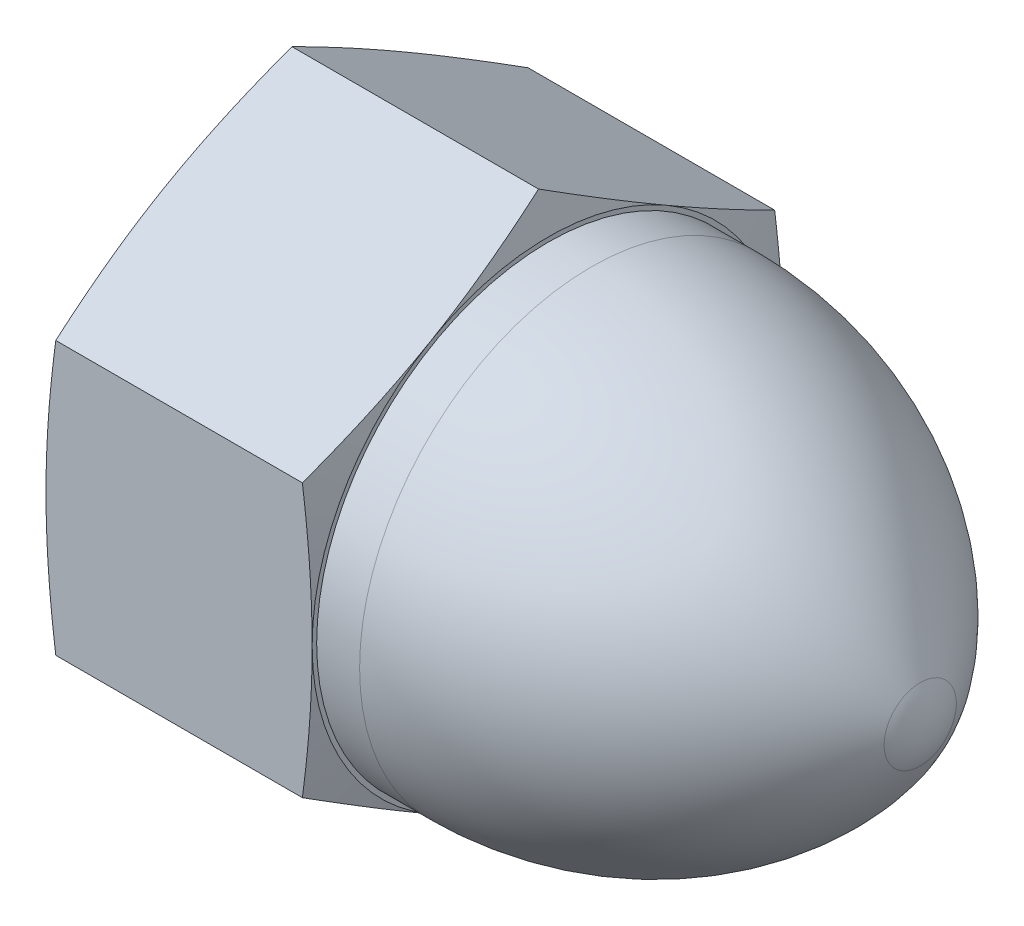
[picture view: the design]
ISO-10303-21;
HEADER;
FILE_DESCRIPTION(('STEP AP214'),'2;1');
FILE_NAME('part.step','',(''),(''),'','','');
FILE_SCHEMA(('AUTOMOTIVE_DESIGN { 1 0 10303 214 1 1 1 1 }'));
ENDSEC;
DATA;
#1=APPLICATION_CONTEXT('core data for automotive mechanical design processes');
#2=APPLICATION_PROTOCOL_DEFINITION('international standard','automotive_design',2000,#1);
#3=PRODUCT_CONTEXT('',#1,'mechanical');
#4=PRODUCT('Part','Part','',(#3));
#5=PRODUCT_RELATED_PRODUCT_CATEGORY('part','',(#4));
#6=PRODUCT_DEFINITION_FORMATION('','',#4);
#7=PRODUCT_DEFINITION_CONTEXT('part definition',#1,'design');
#8=PRODUCT_DEFINITION('design','',#6,#7);
#9=PRODUCT_DEFINITION_SHAPE('','',#8);
#10=(LENGTH_UNIT() NAMED_UNIT(*) SI_UNIT(.MILLI.,.METRE.));
#11=(NAMED_UNIT(*) PLANE_ANGLE_UNIT() SI_UNIT($,.RADIAN.));
#12=(NAMED_UNIT(*) SI_UNIT($,.STERADIAN.) SOLID_ANGLE_UNIT());
#13=UNCERTAINTY_MEASURE_WITH_UNIT(LENGTH_MEASURE(1.E-05),#10,'distance_accuracy_value','');
#14=(GEOMETRIC_REPRESENTATION_CONTEXT(3) GLOBAL_UNCERTAINTY_ASSIGNED_CONTEXT((#13)) GLOBAL_UNIT_ASSIGNED_CONTEXT((#10,
#11,#12)) REPRESENTATION_CONTEXT('',''));
#15=CARTESIAN_POINT('',(0.,0.,0.));
#16=DIRECTION('',(0.,0.,1.));
#17=DIRECTION('',(1.,0.,0.));
#18=AXIS2_PLACEMENT_3D('',#15,#16,#17);
#19=CARTESIAN_POINT('',(20.574,21.0805017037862,0.));
#20=DIRECTION('',(-1.,0.,0.));
#21=DIRECTION('',(0.,0.,1.));
#22=AXIS2_PLACEMENT_3D('',#19,#20,#21);
#23=PLANE('',#22);
#24=CARTESIAN_POINT('',(20.574,0.,0.));
#25=DIRECTION('',(-1.,0.,0.));
#26=DIRECTION('',(0.,0.,1.));
#27=AXIS2_PLACEMENT_3D('',#24,#25,#26);
#28=CIRCLE('',#27,17.907);
#29=CARTESIAN_POINT('',(20.574,0.,17.907));
#30=VERTEX_POINT('',#29);
#31=EDGE_CURVE('E308',#30,#30,#28,.F.);
#32=ORIENTED_EDGE('',*,*,#31,.F.);
#33=EDGE_LOOP('',(#32));
#34=FACE_BOUND('',#33,.T.);
#35=CARTESIAN_POINT('',(20.574,0.,0.));
#36=DIRECTION('',(-1.,0.,0.));
#37=DIRECTION('',(0.,0.,1.));
#38=AXIS2_PLACEMENT_3D('',#35,#36,#37);
#39=CIRCLE('',#38,18.25625);
#40=CARTESIAN_POINT('',(20.574,0.,18.25625));
#41=VERTEX_POINT('',#40);
#42=CARTESIAN_POINT('',(20.574,15.8103762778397,9.12812499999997));
#43=VERTEX_POINT('',#42);
#44=EDGE_CURVE('E279',#41,#43,#39,.T.);
#45=ORIENTED_EDGE('',*,*,#44,.F.);
#46=CARTESIAN_POINT('',(20.574,0.,0.));
#47=DIRECTION('',(-1.,0.,0.));
#48=DIRECTION('',(0.,0.,1.));
#49=AXIS2_PLACEMENT_3D('',#46,#47,#48);
#50=CIRCLE('',#49,18.25625);
#51=CARTESIAN_POINT('',(20.574,-15.8103762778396,9.12812500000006));
#52=VERTEX_POINT('',#51);
#53=EDGE_CURVE('E44',#52,#41,#50,.T.);
#54=ORIENTED_EDGE('',*,*,#53,.F.);
#55=CARTESIAN_POINT('',(20.574,-15.8103762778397,-9.12812499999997));
#56=VERTEX_POINT('',#55);
#57=EDGE_CURVE('E302',#56,#52,#50,.T.);
#58=ORIENTED_EDGE('',*,*,#57,.F.);
#59=CARTESIAN_POINT('',(20.574,0.,-18.25625));
#60=VERTEX_POINT('',#59);
#61=EDGE_CURVE('E360',#60,#56,#50,.T.);
#62=ORIENTED_EDGE('',*,*,#61,.F.);
#63=CARTESIAN_POINT('',(20.574,15.8103762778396,-9.12812500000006));
#64=VERTEX_POINT('',#63);
#65=EDGE_CURVE('E42',#64,#60,#50,.T.);
#66=ORIENTED_EDGE('',*,*,#65,.F.);
#67=EDGE_CURVE('E11',#43,#64,#50,.T.);
#68=ORIENTED_EDGE('',*,*,#67,.F.);
#69=EDGE_LOOP('',(#45,#54,#58,#62,#66,#68));
#70=FACE_BOUND('',#69,.T.);
#71=ADVANCED_FACE('F32',(#34,#70),#23,.F.);
#72=CARTESIAN_POINT('',(0.,0.,0.));
#73=DIRECTION('',(-1.,0.,0.));
#74=DIRECTION('',(0.,0.,1.));
#75=AXIS2_PLACEMENT_3D('',#72,#73,#74);
#76=CYLINDRICAL_SURFACE('',#75,17.907);
#77=CARTESIAN_POINT('',(23.8938672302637,0.,0.));
#78=DIRECTION('',(-1.,0.,0.));
#79=DIRECTION('',(0.,0.,1.));
#80=AXIS2_PLACEMENT_3D('',#77,#78,#79);
#81=CIRCLE('',#80,17.907);
#82=CARTESIAN_POINT('',(23.8938672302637,0.,17.907));
#83=VERTEX_POINT('',#82);
#84=EDGE_CURVE('E326',#83,#83,#81,.T.);
#85=ORIENTED_EDGE('',*,*,#84,.T.);
#86=EDGE_LOOP('',(#85));
#87=FACE_BOUND('',#86,.T.);
#88=ORIENTED_EDGE('',*,*,#31,.T.);
#89=EDGE_LOOP('',(#88));
#90=FACE_BOUND('',#89,.T.);
#91=ADVANCED_FACE('F145',(#87,#90),#76,.T.);
#92=CARTESIAN_POINT('',(23.8938672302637,0.,0.));
#93=DIRECTION('',(-1.,0.,0.));
#94=DIRECTION('',(0.,0.,1.));
#95=AXIS2_PLACEMENT_3D('',#92,#93,#94);
#96=DEGENERATE_TOROIDAL_SURFACE('',#95,11.049,28.956,.F.);
#97=ORIENTED_EDGE('',*,*,#84,.F.);
#98=EDGE_LOOP('',(#97));
#99=FACE_BOUND('',#98,.T.);
#100=CARTESIAN_POINT('',(49.3273082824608,0.,0.));
#101=DIRECTION('',(-1.,0.,0.));
#102=DIRECTION('',(0.,0.,1.));
#103=AXIS2_PLACEMENT_3D('',#100,#101,#102);
#104=CIRCLE('',#103,2.7926043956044);
#105=CARTESIAN_POINT('',(49.3273082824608,0.,2.7926043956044));
#106=VERTEX_POINT('',#105);
#107=EDGE_CURVE('E330',#106,#106,#104,.T.);
#108=ORIENTED_EDGE('',*,*,#107,.T.);
#109=EDGE_LOOP('',(#108));
#110=FACE_BOUND('',#109,.T.);
#111=ADVANCED_FACE('F151',(#99,#110),#96,.F.);
#112=CARTESIAN_POINT('',(44.196,0.,0.));
#113=DIRECTION('',(-1.,0.,0.));
#114=DIRECTION('',(0.,1.,0.));
#115=AXIS2_PLACEMENT_3D('',#112,#113,#114);
#116=SPHERICAL_SURFACE('',#115,5.842);
#117=ORIENTED_EDGE('',*,*,#107,.F.);
#118=EDGE_LOOP('',(#117));
#119=FACE_BOUND('',#118,.T.);
#120=ADVANCED_FACE('F210',(#119),#116,.T.);
#121=CARTESIAN_POINT('',(18.6244609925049,0.,0.));
#122=DIRECTION('',(-1.,0.,0.));
#123=DIRECTION('',(0.,0.,1.));
#124=AXIS2_PLACEMENT_3D('',#121,#122,#123);
#125=CONICAL_SURFACE('',#124,25.5333499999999,1.30904233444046);
#126=CARTESIAN_POINT('',(16.5206177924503,-27.9528666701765,18.25625));
#127=CARTESIAN_POINT('',(16.613591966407,-27.5383510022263,18.25625));
#128=CARTESIAN_POINT('',(16.7059811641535,-27.1237041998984,18.25625));
#129=CARTESIAN_POINT('',(16.8894610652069,-26.2941220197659,18.25625));
#130=CARTESIAN_POINT('',(16.9805517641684,-25.8791866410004,18.25625));
#131=CARTESIAN_POINT('',(17.2516895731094,-24.6338792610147,18.25625));
#132=CARTESIAN_POINT('',(17.4295949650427,-23.8030390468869,18.25625));
#133=CARTESIAN_POINT('',(17.7785811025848,-22.1390834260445,18.25625));
#134=CARTESIAN_POINT('',(17.9496550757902,-21.3059665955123,18.25625));
#135=CARTESIAN_POINT('',(18.2831573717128,-19.6380047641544,18.25625));
#136=CARTESIAN_POINT('',(18.4455857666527,-18.8031597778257,18.25625));
#137=CARTESIAN_POINT('',(18.758479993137,-17.1380988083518,18.25625));
#138=CARTESIAN_POINT('',(18.9090307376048,-16.3078988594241,18.25625));
#139=CARTESIAN_POINT('',(19.1970690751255,-14.645217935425,18.25625));
#140=CARTESIAN_POINT('',(19.3345566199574,-13.8127369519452,18.25625));
#141=CARTESIAN_POINT('',(19.5933814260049,-12.1453557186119,18.25625));
#142=CARTESIAN_POINT('',(19.7147207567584,-11.3104557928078,18.25625));
#143=CARTESIAN_POINT('',(19.9376884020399,-9.63799782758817,18.25625));
#144=CARTESIAN_POINT('',(20.0393166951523,-8.80043978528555,18.25625));
#145=CARTESIAN_POINT('',(20.2199995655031,-7.11319028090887,18.25625));
#146=CARTESIAN_POINT('',(20.2987834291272,-6.26346939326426,18.25625));
#147=CARTESIAN_POINT('',(20.4283525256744,-4.56187709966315,18.25625));
#148=CARTESIAN_POINT('',(20.4791384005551,-3.71000574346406,18.25625));
#149=CARTESIAN_POINT('',(20.5497504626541,-2.0053499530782,18.25625));
#150=CARTESIAN_POINT('',(20.569590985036,-1.15256612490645,18.25625));
#151=CARTESIAN_POINT('',(20.5770909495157,0.553144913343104,18.25625));
#152=CARTESIAN_POINT('',(20.5647504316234,1.40607212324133,18.25625));
#153=CARTESIAN_POINT('',(20.5085815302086,3.1139827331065,18.25625));
#154=CARTESIAN_POINT('',(20.4646384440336,3.96896228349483,18.25625));
#155=CARTESIAN_POINT('',(20.3477789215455,5.67692075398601,18.25625));
#156=CARTESIAN_POINT('',(20.2748618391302,6.52989962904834,18.25625));
#157=CARTESIAN_POINT('',(20.1037548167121,8.23384807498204,18.25625));
#158=CARTESIAN_POINT('',(20.0055482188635,9.08481594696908,18.25625));
#159=CARTESIAN_POINT('',(19.7879699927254,10.7840112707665,18.25625));
#160=CARTESIAN_POINT('',(19.668598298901,11.6322387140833,18.25625));
#161=CARTESIAN_POINT('',(19.42007434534,13.2761312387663,18.25625));
#162=CARTESIAN_POINT('',(19.2919132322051,14.0719476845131,18.25625));
#163=CARTESIAN_POINT('',(19.0230220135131,15.6614648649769,18.25625));
#164=CARTESIAN_POINT('',(18.8822915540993,16.4551655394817,18.25625));
#165=CARTESIAN_POINT('',(18.5905739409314,18.0407555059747,18.25625));
#166=CARTESIAN_POINT('',(18.4395857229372,18.8326446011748,18.25625));
#167=CARTESIAN_POINT('',(18.1292586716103,20.4147711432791,18.25625));
#168=CARTESIAN_POINT('',(17.9699199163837,21.2050086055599,18.25625));
#169=CARTESIAN_POINT('',(17.6443692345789,22.7842687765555,18.25625));
#170=CARTESIAN_POINT('',(17.4781555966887,23.5732911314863,18.25625));
#171=CARTESIAN_POINT('',(17.1401060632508,25.1501292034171,18.25625));
#172=CARTESIAN_POINT('',(16.9682701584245,25.9379449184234,18.25625));
#173=CARTESIAN_POINT('',(16.6199584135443,27.5124939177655,18.25625));
#174=CARTESIAN_POINT('',(16.4434828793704,28.2992272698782,18.25625));
#175=CARTESIAN_POINT('',(16.0866504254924,29.8718140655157,18.25625));
#176=CARTESIAN_POINT('',(15.9062934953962,30.6576675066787,18.25625));
#177=CARTESIAN_POINT('',(15.3639661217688,32.99856785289,18.25625));
#178=CARTESIAN_POINT('',(14.9972674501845,34.5525192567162,18.25625));
#179=CARTESIAN_POINT('',(14.2547452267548,37.6582621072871,18.25625));
#180=CARTESIAN_POINT('',(13.8789215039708,39.2100535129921,18.25625));
#181=CARTESIAN_POINT('',(13.1209857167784,42.3100255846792,18.25625));
#182=CARTESIAN_POINT('',(12.7388821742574,43.8582083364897,18.25625));
#183=CARTESIAN_POINT('',(12.1618933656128,46.1795005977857,18.25625));
#184=CARTESIAN_POINT('',(11.9689280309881,46.9530884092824,18.25625));
#185=CARTESIAN_POINT('',(11.5818653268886,48.4999799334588,18.25625));
#186=CARTESIAN_POINT('',(11.3877679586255,49.2732836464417,18.25625));
#187=CARTESIAN_POINT('',(11.1931782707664,50.0464635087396,18.25625));
#188=B_SPLINE_CURVE_WITH_KNOTS('',3,(#126,#127,#128,#129,#130,#131,#132,#133,#134,#135,#136,
#137,#138,#139,#140,#141,#142,#143,#144,#145,#146,#147,#148,#149,#150,#151,#152,#153,#154,#155,
#156,#157,#158,#159,#160,#161,#162,#163,#164,#165,#166,#167,#168,#169,#170,#171,#172,#173,#174,
#175,#176,#177,#178,#179,#180,#181,#182,#183,#184,#185,#186,#187),.UNSPECIFIED.,.F.,.F.,(4,2,2,
2,2,2,2,2,2,2,2,2,2,2,2,2,2,2,2,2,2,2,2,2,2,2,2,2,2,2,4),(0.,1.2744429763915,2.54889021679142,
5.09788626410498,7.6493495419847,10.2007915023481,12.731928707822,15.2630752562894,
17.7938971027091,20.3247216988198,22.8844145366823,25.4440486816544,28.0024967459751,
30.5609416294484,33.1287196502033,35.6965549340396,38.2660859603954,40.835624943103,
43.2537161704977,45.671875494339,48.0902860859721,50.5086740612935,52.9276676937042,
55.3466653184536,57.7655038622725,60.1843488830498,64.9741997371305,69.7641403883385,
74.5480444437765,76.9399183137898,79.3317896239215),.UNSPECIFIED.);
#189=CARTESIAN_POINT('',(19.8173814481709,-10.5402508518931,18.25625));
#190=VERTEX_POINT('',#189);
#191=EDGE_CURVE('E233',#41,#190,#188,.F.);
#192=ORIENTED_EDGE('',*,*,#191,.T.);
#193=CARTESIAN_POINT('',(19.8173505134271,-10.5401353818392,18.25645));
#194=CARTESIAN_POINT('',(19.8759853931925,-10.7590105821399,17.8773470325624));
#195=CARTESIAN_POINT('',(19.9319340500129,-10.978065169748,17.4979333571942));
#196=CARTESIAN_POINT('',(20.0379028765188,-11.4165429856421,16.7384675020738));
#197=CARTESIAN_POINT('',(20.0879227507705,-11.6359662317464,16.3584152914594));
#198=CARTESIAN_POINT('',(20.2282800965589,-12.2949280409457,15.2170599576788));
#199=CARTESIAN_POINT('',(20.3088725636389,-12.7350021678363,14.4548292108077));
#200=CARTESIAN_POINT('',(20.4394715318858,-13.6140162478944,12.9323321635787));
#201=CARTESIAN_POINT('',(20.4896336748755,-14.0529503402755,12.1720760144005));
#202=CARTESIAN_POINT('',(20.5568947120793,-14.9313817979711,10.650588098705));
#203=CARTESIAN_POINT('',(20.574,-15.3708790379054,9.88935654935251));
#204=CARTESIAN_POINT('',(20.574,-16.249873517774,8.36689345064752));
#205=CARTESIAN_POINT('',(20.5568947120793,-16.6893707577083,7.60566190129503));
#206=CARTESIAN_POINT('',(20.4896336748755,-17.5678022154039,6.08417398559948));
#207=CARTESIAN_POINT('',(20.4394715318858,-18.0067363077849,5.32391783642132));
#208=CARTESIAN_POINT('',(20.3088725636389,-18.885750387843,3.80142078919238));
#209=CARTESIAN_POINT('',(20.2282800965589,-19.3258245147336,3.03919004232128));
#210=CARTESIAN_POINT('',(20.0879227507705,-19.9847863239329,1.89783470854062));
#211=CARTESIAN_POINT('',(20.0379028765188,-20.2042095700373,1.51778249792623));
#212=CARTESIAN_POINT('',(19.9319340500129,-20.6426873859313,0.758316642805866));
#213=CARTESIAN_POINT('',(19.8759853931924,-20.8617419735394,0.37890296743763));
#214=CARTESIAN_POINT('',(19.8173505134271,-21.0806171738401,-0.000199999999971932));
#215=B_SPLINE_CURVE_WITH_KNOTS('',3,(#193,#194,#195,#196,#197,#198,#199,#200,#201,#202,#203,
#204,#205,#206,#207,#208,#209,#210,#211,#212,#213,#214),.UNSPECIFIED.,.F.,.F.,(4,2,2,2,2,2,2,2,
2,2,4),(0.,1.32496515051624,2.64999629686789,5.30100599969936,7.93833969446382,10.5751632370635,
13.2119867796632,15.8493204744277,18.5003301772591,19.8253613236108,21.150326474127),.UNSPECIFIED.);
#216=EDGE_CURVE('E231',#190,#52,#215,.T.);
#217=ORIENTED_EDGE('',*,*,#216,.T.);
#218=ORIENTED_EDGE('',*,*,#53,.T.);
#219=EDGE_LOOP('',(#192,#217,#218));
#220=FACE_BOUND('',#219,.T.);
#221=ADVANCED_FACE('F356',(#220),#125,.T.);
#222=CARTESIAN_POINT('',(19.8173814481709,-21.0805017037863,0.));
#223=VERTEX_POINT('',#222);
#224=EDGE_CURVE('E226',#52,#223,#215,.T.);
#225=ORIENTED_EDGE('',*,*,#224,.T.);
#226=CARTESIAN_POINT('',(19.8173505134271,-21.0806171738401,0.000200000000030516));
#227=CARTESIAN_POINT('',(19.8759853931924,-20.8617419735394,-0.378902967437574));
#228=CARTESIAN_POINT('',(19.9319340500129,-20.6426873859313,-0.758316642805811));
#229=CARTESIAN_POINT('',(20.0379028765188,-20.2042095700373,-1.51778249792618));
#230=CARTESIAN_POINT('',(20.0879227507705,-19.9847863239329,-1.89783470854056));
#231=CARTESIAN_POINT('',(20.2282800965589,-19.3258245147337,-3.03919004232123));
#232=CARTESIAN_POINT('',(20.3088725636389,-18.885750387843,-3.80142078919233));
#233=CARTESIAN_POINT('',(20.4394715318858,-18.006736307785,-5.32391783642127));
#234=CARTESIAN_POINT('',(20.4896336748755,-17.5678022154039,-6.08417398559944));
#235=CARTESIAN_POINT('',(20.5568947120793,-16.6893707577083,-7.60566190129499));
#236=CARTESIAN_POINT('',(20.574,-16.249873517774,-8.36689345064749));
#237=CARTESIAN_POINT('',(20.574,-15.3708790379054,-9.88935654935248));
#238=CARTESIAN_POINT('',(20.5568947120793,-14.9313817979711,-10.650588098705));
#239=CARTESIAN_POINT('',(20.4896336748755,-14.0529503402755,-12.1720760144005));
#240=CARTESIAN_POINT('',(20.4394715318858,-13.6140162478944,-12.9323321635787));
#241=CARTESIAN_POINT('',(20.3088725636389,-12.7350021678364,-14.4548292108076));
#242=CARTESIAN_POINT('',(20.2282800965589,-12.2949280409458,-15.2170599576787));
#243=CARTESIAN_POINT('',(20.0879227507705,-11.6359662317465,-16.3584152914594));
#244=CARTESIAN_POINT('',(20.0379028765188,-11.4165429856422,-16.7384675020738));
#245=CARTESIAN_POINT('',(19.9319340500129,-10.9780651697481,-17.4979333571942));
#246=CARTESIAN_POINT('',(19.8759853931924,-10.75901058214,-17.8773470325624));
#247=CARTESIAN_POINT('',(19.8173505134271,-10.5401353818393,-18.25645));
#248=B_SPLINE_CURVE_WITH_KNOTS('',3,(#226,#227,#228,#229,#230,#231,#232,#233,#234,#235,#236,
#237,#238,#239,#240,#241,#242,#243,#244,#245,#246,#247),.UNSPECIFIED.,.F.,.F.,(4,2,2,2,2,2,2,2,
2,2,4),(0.,1.32496515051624,2.64999629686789,5.30100599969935,7.93833969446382,10.5751632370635,
13.2119867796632,15.8493204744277,18.5003301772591,19.8253613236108,21.150326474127),.UNSPECIFIED.);
#249=EDGE_CURVE('E232',#223,#56,#248,.T.);
#250=ORIENTED_EDGE('',*,*,#249,.T.);
#251=ORIENTED_EDGE('',*,*,#57,.T.);
#252=EDGE_LOOP('',(#225,#250,#251));
#253=FACE_BOUND('',#252,.T.);
#254=ADVANCED_FACE('F362',(#253),#125,.T.);
#255=CARTESIAN_POINT('',(19.8173814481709,-10.5402508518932,-18.25625));
#256=VERTEX_POINT('',#255);
#257=EDGE_CURVE('E221',#56,#256,#248,.T.);
#258=ORIENTED_EDGE('',*,*,#257,.T.);
#259=CARTESIAN_POINT('',(16.5206177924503,-27.9528666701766,-18.25625));
#260=CARTESIAN_POINT('',(16.613591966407,-27.5383510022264,-18.25625));
#261=CARTESIAN_POINT('',(16.7059811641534,-27.1237041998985,-18.25625));
#262=CARTESIAN_POINT('',(16.8894610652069,-26.294122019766,-18.25625));
#263=CARTESIAN_POINT('',(16.9805517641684,-25.8791866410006,-18.25625));
#264=CARTESIAN_POINT('',(17.2516895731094,-24.6338792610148,-18.25625));
#265=CARTESIAN_POINT('',(17.4295949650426,-23.803039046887,-18.25625));
#266=CARTESIAN_POINT('',(17.7785811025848,-22.1390834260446,-18.25625));
#267=CARTESIAN_POINT('',(17.9496550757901,-21.3059665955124,-18.25625));
#268=CARTESIAN_POINT('',(18.2831573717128,-19.6380047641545,-18.25625));
#269=CARTESIAN_POINT('',(18.4455857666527,-18.8031597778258,-18.25625));
#270=CARTESIAN_POINT('',(18.758479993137,-17.138098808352,-18.25625));
#271=CARTESIAN_POINT('',(18.9090307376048,-16.3078988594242,-18.25625));
#272=CARTESIAN_POINT('',(19.1970690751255,-14.6452179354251,-18.25625));
#273=CARTESIAN_POINT('',(19.3345566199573,-13.8127369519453,-18.25625));
#274=CARTESIAN_POINT('',(19.5933814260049,-12.145355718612,-18.25625));
#275=CARTESIAN_POINT('',(19.7147207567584,-11.3104557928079,-18.25625));
#276=CARTESIAN_POINT('',(19.9376884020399,-9.63799782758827,-18.25625));
#277=CARTESIAN_POINT('',(20.0393166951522,-8.80043978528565,-18.25625));
#278=CARTESIAN_POINT('',(20.2199995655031,-7.11319028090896,-18.25625));
#279=CARTESIAN_POINT('',(20.2987834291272,-6.26346939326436,-18.25625));
#280=CARTESIAN_POINT('',(20.4283525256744,-4.56187709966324,-18.25625));
#281=CARTESIAN_POINT('',(20.4791384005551,-3.71000574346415,-18.25625));
#282=CARTESIAN_POINT('',(20.5497504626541,-2.00534995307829,-18.25625));
#283=CARTESIAN_POINT('',(20.569590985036,-1.15256612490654,-18.25625));
#284=CARTESIAN_POINT('',(20.5770909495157,0.55314491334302,-18.25625));
#285=CARTESIAN_POINT('',(20.5647504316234,1.40607212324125,-18.25625));
#286=CARTESIAN_POINT('',(20.5085815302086,3.11398273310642,-18.25625));
#287=CARTESIAN_POINT('',(20.4646384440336,3.96896228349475,-18.25625));
#288=CARTESIAN_POINT('',(20.3477789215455,5.67692075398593,-18.25625));
#289=CARTESIAN_POINT('',(20.2748618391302,6.52989962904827,-18.25625));
#290=CARTESIAN_POINT('',(20.1037548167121,8.23384807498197,-18.25625));
#291=CARTESIAN_POINT('',(20.0055482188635,9.08481594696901,-18.25625));
#292=CARTESIAN_POINT('',(19.7879699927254,10.7840112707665,-18.25625));
#293=CARTESIAN_POINT('',(19.668598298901,11.6322387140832,-18.25625));
#294=CARTESIAN_POINT('',(19.42007434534,13.2761312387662,-18.25625));
#295=CARTESIAN_POINT('',(19.2919132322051,14.071947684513,-18.25625));
#296=CARTESIAN_POINT('',(19.0230220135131,15.6614648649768,-18.25625));
#297=CARTESIAN_POINT('',(18.8822915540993,16.4551655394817,-18.25625));
#298=CARTESIAN_POINT('',(18.5905739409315,18.0407555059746,-18.25625));
#299=CARTESIAN_POINT('',(18.4395857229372,18.8326446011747,-18.25625));
#300=CARTESIAN_POINT('',(18.1292586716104,20.4147711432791,-18.25625));
#301=CARTESIAN_POINT('',(17.9699199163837,21.2050086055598,-18.25625));
#302=CARTESIAN_POINT('',(17.6443692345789,22.7842687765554,-18.25625));
#303=CARTESIAN_POINT('',(17.4781555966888,23.5732911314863,-18.25625));
#304=CARTESIAN_POINT('',(17.1401060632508,25.150129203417,-18.25625));
#305=CARTESIAN_POINT('',(16.9682701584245,25.9379449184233,-18.25625));
#306=CARTESIAN_POINT('',(16.6199584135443,27.5124939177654,-18.25625));
#307=CARTESIAN_POINT('',(16.4434828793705,28.2992272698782,-18.25625));
#308=CARTESIAN_POINT('',(16.0866504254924,29.8718140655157,-18.25625));
#309=CARTESIAN_POINT('',(15.9062934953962,30.6576675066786,-18.25625));
#310=CARTESIAN_POINT('',(15.3639661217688,32.9985678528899,-18.25625));
#311=CARTESIAN_POINT('',(14.9972674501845,34.5525192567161,-18.25625));
#312=CARTESIAN_POINT('',(14.2547452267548,37.658262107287,-18.25625));
#313=CARTESIAN_POINT('',(13.8789215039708,39.210053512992,-18.25625));
#314=CARTESIAN_POINT('',(13.1209857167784,42.3100255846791,-18.25625));
#315=CARTESIAN_POINT('',(12.7388821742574,43.8582083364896,-18.25625));
#316=CARTESIAN_POINT('',(12.1618933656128,46.1795005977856,-18.25625));
#317=CARTESIAN_POINT('',(11.9689280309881,46.9530884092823,-18.25625));
#318=CARTESIAN_POINT('',(11.5818653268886,48.4999799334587,-18.25625));
#319=CARTESIAN_POINT('',(11.3877679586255,49.2732836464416,-18.25625));
#320=CARTESIAN_POINT('',(11.1931782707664,50.0464635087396,-18.25625));
#321=B_SPLINE_CURVE_WITH_KNOTS('',3,(#259,#260,#261,#262,#263,#264,#265,#266,#267,#268,#269,
#270,#271,#272,#273,#274,#275,#276,#277,#278,#279,#280,#281,#282,#283,#284,#285,#286,#287,#288,
#289,#290,#291,#292,#293,#294,#295,#296,#297,#298,#299,#300,#301,#302,#303,#304,#305,#306,#307,
#308,#309,#310,#311,#312,#313,#314,#315,#316,#317,#318,#319,#320),.UNSPECIFIED.,.F.,.F.,(4,2,2,
2,2,2,2,2,2,2,2,2,2,2,2,2,2,2,2,2,2,2,2,2,2,2,2,2,2,2,4),(0.,1.2744429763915,2.54889021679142,
5.09788626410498,7.64934954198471,10.2007915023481,12.731928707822,15.2630752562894,
17.7938971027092,20.3247216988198,22.8844145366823,25.4440486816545,28.0024967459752,
30.5609416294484,33.1287196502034,35.6965549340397,38.2660859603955,40.8356249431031,
43.2537161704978,45.6718754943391,48.0902860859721,50.5086740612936,52.9276676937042,
55.3466653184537,57.7655038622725,60.1843488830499,64.9741997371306,69.7641403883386,
74.5480444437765,76.9399183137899,79.3317896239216),.UNSPECIFIED.);
#322=EDGE_CURVE('E58',#60,#256,#321,.F.);
#323=ORIENTED_EDGE('',*,*,#322,.F.);
#324=ORIENTED_EDGE('',*,*,#61,.T.);
#325=EDGE_LOOP('',(#258,#323,#324));
#326=FACE_BOUND('',#325,.T.);
#327=ADVANCED_FACE('F206',(#326),#125,.T.);
#328=CARTESIAN_POINT('',(19.8173505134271,10.5401353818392,-18.25645));
#329=CARTESIAN_POINT('',(19.8759853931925,10.7590105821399,-17.8773470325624));
#330=CARTESIAN_POINT('',(19.9319340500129,10.978065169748,-17.4979333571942));
#331=CARTESIAN_POINT('',(20.0379028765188,11.4165429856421,-16.7384675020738));
#332=CARTESIAN_POINT('',(20.0879227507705,11.6359662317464,-16.3584152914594));
#333=CARTESIAN_POINT('',(20.2282800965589,12.2949280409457,-15.2170599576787));
#334=CARTESIAN_POINT('',(20.3088725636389,12.7350021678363,-14.4548292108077));
#335=CARTESIAN_POINT('',(20.4394715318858,13.6140162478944,-12.9323321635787));
#336=CARTESIAN_POINT('',(20.4896336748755,14.0529503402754,-12.1720760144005));
#337=CARTESIAN_POINT('',(20.5568947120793,14.931381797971,-10.650588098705));
#338=CARTESIAN_POINT('',(20.574,15.3708790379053,-9.88935654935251));
#339=CARTESIAN_POINT('',(20.574,16.2498735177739,-8.36689345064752));
#340=CARTESIAN_POINT('',(20.5568947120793,16.6893707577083,-7.60566190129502));
#341=CARTESIAN_POINT('',(20.4896336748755,17.5678022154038,-6.08417398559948));
#342=CARTESIAN_POINT('',(20.4394715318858,18.0067363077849,-5.32391783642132));
#343=CARTESIAN_POINT('',(20.3088725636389,18.885750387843,-3.80142078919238));
#344=CARTESIAN_POINT('',(20.2282800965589,19.3258245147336,-3.03919004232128));
#345=CARTESIAN_POINT('',(20.0879227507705,19.9847863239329,-1.89783470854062));
#346=CARTESIAN_POINT('',(20.0379028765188,20.2042095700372,-1.51778249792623));
#347=CARTESIAN_POINT('',(19.9319340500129,20.6426873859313,-0.758316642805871));
#348=CARTESIAN_POINT('',(19.8759853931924,20.8617419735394,-0.378902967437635));
#349=CARTESIAN_POINT('',(19.8173505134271,21.0806171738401,0.00019999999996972));
#350=B_SPLINE_CURVE_WITH_KNOTS('',3,(#328,#329,#330,#331,#332,#333,#334,#335,#336,#337,#338,
#339,#340,#341,#342,#343,#344,#345,#346,#347,#348,#349),.UNSPECIFIED.,.F.,.F.,(4,2,2,2,2,2,2,2,
2,2,4),(0.,1.32496515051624,2.64999629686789,5.30100599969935,7.93833969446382,10.5751632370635,
13.2119867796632,15.8493204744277,18.5003301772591,19.8253613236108,21.150326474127),.UNSPECIFIED.);
#351=CARTESIAN_POINT('',(19.8173814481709,10.5402508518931,-18.25625));
#352=VERTEX_POINT('',#351);
#353=EDGE_CURVE('E189',#352,#64,#350,.T.);
#354=ORIENTED_EDGE('',*,*,#353,.T.);
#355=ORIENTED_EDGE('',*,*,#65,.T.);
#356=EDGE_CURVE('E196',#352,#60,#321,.F.);
#357=ORIENTED_EDGE('',*,*,#356,.F.);
#358=EDGE_LOOP('',(#354,#355,#357));
#359=FACE_BOUND('',#358,.T.);
#360=ADVANCED_FACE('F201',(#359),#125,.T.);
#361=CARTESIAN_POINT('',(19.8173505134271,21.0806171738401,-0.000200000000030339));
#362=CARTESIAN_POINT('',(19.8759853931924,20.8617419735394,0.378902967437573));
#363=CARTESIAN_POINT('',(19.9319340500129,20.6426873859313,0.758316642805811));
#364=CARTESIAN_POINT('',(20.0379028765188,20.2042095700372,1.51778249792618));
#365=CARTESIAN_POINT('',(20.0879227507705,19.9847863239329,1.89783470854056));
#366=CARTESIAN_POINT('',(20.2282800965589,19.3258245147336,3.03919004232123));
#367=CARTESIAN_POINT('',(20.3088725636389,18.885750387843,3.80142078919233));
#368=CARTESIAN_POINT('',(20.4394715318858,18.006736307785,5.32391783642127));
#369=CARTESIAN_POINT('',(20.4896336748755,17.5678022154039,6.08417398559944));
#370=CARTESIAN_POINT('',(20.5568947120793,16.6893707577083,7.60566190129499));
#371=CARTESIAN_POINT('',(20.574,16.249873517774,8.36689345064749));
#372=CARTESIAN_POINT('',(20.574,15.3708790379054,9.88935654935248));
#373=CARTESIAN_POINT('',(20.5568947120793,14.9313817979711,10.650588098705));
#374=CARTESIAN_POINT('',(20.4896336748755,14.0529503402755,12.1720760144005));
#375=CARTESIAN_POINT('',(20.4394715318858,13.6140162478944,12.9323321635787));
#376=CARTESIAN_POINT('',(20.3088725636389,12.7350021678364,14.4548292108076));
#377=CARTESIAN_POINT('',(20.2282800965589,12.2949280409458,15.2170599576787));
#378=CARTESIAN_POINT('',(20.0879227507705,11.6359662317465,16.3584152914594));
#379=CARTESIAN_POINT('',(20.0379028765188,11.4165429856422,16.7384675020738));
#380=CARTESIAN_POINT('',(19.9319340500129,10.9780651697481,17.4979333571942));
#381=CARTESIAN_POINT('',(19.8759853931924,10.75901058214,17.8773470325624));
#382=CARTESIAN_POINT('',(19.8173505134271,10.5401353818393,18.25645));
#383=B_SPLINE_CURVE_WITH_KNOTS('',3,(#361,#362,#363,#364,#365,#366,#367,#368,#369,#370,#371,
#372,#373,#374,#375,#376,#377,#378,#379,#380,#381,#382),.UNSPECIFIED.,.F.,.F.,(4,2,2,2,2,2,2,2,
2,2,4),(0.,1.32496515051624,2.64999629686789,5.30100599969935,7.93833969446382,10.5751632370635,
13.2119867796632,15.8493204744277,18.5003301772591,19.8253613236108,21.150326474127),.UNSPECIFIED.);
#384=CARTESIAN_POINT('',(19.8173814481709,21.0805017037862,0.));
#385=VERTEX_POINT('',#384);
#386=EDGE_CURVE('E50',#385,#43,#383,.T.);
#387=ORIENTED_EDGE('',*,*,#386,.T.);
#388=ORIENTED_EDGE('',*,*,#67,.T.);
#389=EDGE_CURVE('E182',#64,#385,#350,.T.);
#390=ORIENTED_EDGE('',*,*,#389,.T.);
#391=EDGE_LOOP('',(#387,#388,#390));
#392=FACE_BOUND('',#391,.T.);
#393=ADVANCED_FACE('F205',(#392),#125,.T.);
#394=CARTESIAN_POINT('',(19.8173814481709,10.5402508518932,18.25625));
#395=VERTEX_POINT('',#394);
#396=EDGE_CURVE('E332',#43,#395,#383,.T.);
#397=ORIENTED_EDGE('',*,*,#396,.T.);
#398=EDGE_CURVE('E335',#395,#41,#188,.F.);
#399=ORIENTED_EDGE('',*,*,#398,.T.);
#400=ORIENTED_EDGE('',*,*,#44,.T.);
#401=EDGE_LOOP('',(#397,#399,#400));
#402=FACE_BOUND('',#401,.T.);
#403=ADVANCED_FACE('F168',(#402),#125,.T.);
#404=CARTESIAN_POINT('',(20.574,10.5402508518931,-18.25625));
#405=DIRECTION('',(0.,-0.866025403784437,0.500000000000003));
#406=DIRECTION('',(0.,-0.500000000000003,-0.866025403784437));
#407=AXIS2_PLACEMENT_3D('',#404,#405,#406);
#408=PLANE('',#407);
#409=ORIENTED_EDGE('',*,*,#353,.F.);
#410=DIRECTION('',(-1.,0.,0.));
#411=VECTOR('',#410,1.);
#412=CARTESIAN_POINT('',(20.574,10.5402508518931,-18.25625));
#413=LINE('',#412,#411);
#414=CARTESIAN_POINT('',(0.75675596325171,10.5402508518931,-18.25625));
#415=VERTEX_POINT('',#414);
#416=EDGE_CURVE('E321',#352,#415,#413,.T.);
#417=ORIENTED_EDGE('',*,*,#416,.T.);
#418=CARTESIAN_POINT('',(0.756786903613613,21.0806171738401,0.000199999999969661));
#419=CARTESIAN_POINT('',(0.698141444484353,20.8617422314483,-0.378902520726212));
#420=CARTESIAN_POINT('',(0.64218267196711,20.6426878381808,-0.758315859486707));
#421=CARTESIAN_POINT('',(0.536194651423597,20.204210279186,-1.51778126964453));
#422=CARTESIAN_POINT('',(0.48616569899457,19.9847870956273,-1.8978333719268));
#423=CARTESIAN_POINT('',(0.345782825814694,19.3258252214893,-3.03918881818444));
#424=CARTESIAN_POINT('',(0.265175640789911,18.8857507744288,-3.80142011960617));
#425=CARTESIAN_POINT('',(0.134552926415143,18.0067364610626,-5.32391757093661));
#426=CARTESIAN_POINT('',(0.084381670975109,17.5678024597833,-6.08417356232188));
#427=CARTESIAN_POINT('',(0.0171084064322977,16.6893709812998,-7.60566151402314));
#428=CARTESIAN_POINT('',(0.,16.2498736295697,-8.36689325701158));
#429=CARTESIAN_POINT('',(0.,15.3708789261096,-9.88935674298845));
#430=CARTESIAN_POINT('',(0.0171084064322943,14.9313815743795,-10.6505884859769));
#431=CARTESIAN_POINT('',(0.0843816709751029,14.052950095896,-12.1720764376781));
#432=CARTESIAN_POINT('',(0.134552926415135,13.6140160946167,-12.9323324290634));
#433=CARTESIAN_POINT('',(0.265175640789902,12.7350017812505,-14.4548298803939));
#434=CARTESIAN_POINT('',(0.345782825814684,12.2949273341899,-15.2170611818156));
#435=CARTESIAN_POINT('',(0.486165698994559,11.635965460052,-16.3584166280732));
#436=CARTESIAN_POINT('',(0.536194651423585,11.4165422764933,-16.7384687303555));
#437=CARTESIAN_POINT('',(0.642182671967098,10.9780647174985,-17.4979341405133));
#438=CARTESIAN_POINT('',(0.698141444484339,10.7590103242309,-17.8773474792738));
#439=CARTESIAN_POINT('',(0.756786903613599,10.5401353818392,-18.25645));
#440=B_SPLINE_CURVE_WITH_KNOTS('',3,(#418,#419,#420,#421,#422,#423,#424,#425,#426,#427,#428,
#429,#430,#431,#432,#433,#434,#435,#436,#437,#438,#439),.UNSPECIFIED.,.F.,.F.,(4,2,2,2,2,2,2,2,
2,2,4),(0.,1.32496782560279,2.6500016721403,5.30101714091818,7.93835164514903,10.5751758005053,
13.2119999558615,15.8493344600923,18.5003499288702,19.8253837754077,21.1503516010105),.UNSPECIFIED.);
#441=CARTESIAN_POINT('',(0.,15.8103762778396,-9.12812500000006));
#442=VERTEX_POINT('',#441);
#443=EDGE_CURVE('E174',#442,#415,#440,.T.);
#444=ORIENTED_EDGE('',*,*,#443,.F.);
#445=CARTESIAN_POINT('',(0.756755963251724,21.0805017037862,0.));
#446=VERTEX_POINT('',#445);
#447=EDGE_CURVE('E269',#446,#442,#440,.T.);
#448=ORIENTED_EDGE('',*,*,#447,.F.);
#449=DIRECTION('',(-1.,0.,0.));
#450=VECTOR('',#449,1.);
#451=CARTESIAN_POINT('',(20.574,21.0805017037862,0.));
#452=LINE('',#451,#450);
#453=EDGE_CURVE('E323',#385,#446,#452,.T.);
#454=ORIENTED_EDGE('',*,*,#453,.F.);
#455=ORIENTED_EDGE('',*,*,#389,.F.);
#456=EDGE_LOOP('',(#409,#417,#444,#448,#454,#455));
#457=FACE_BOUND('',#456,.T.);
#458=ADVANCED_FACE('F163',(#457),#408,.F.);
#459=CARTESIAN_POINT('',(20.574,10.5402508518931,-18.25625));
#460=DIRECTION('',(0.,0.,-1.));
#461=DIRECTION('',(-1.,0.,0.));
#462=AXIS2_PLACEMENT_3D('',#459,#460,#461);
#463=PLANE('',#462);
#464=ORIENTED_EDGE('',*,*,#416,.F.);
#465=ORIENTED_EDGE('',*,*,#356,.T.);
#466=ORIENTED_EDGE('',*,*,#322,.T.);
#467=DIRECTION('',(-1.,0.,0.));
#468=VECTOR('',#467,1.);
#469=CARTESIAN_POINT('',(20.574,-10.5402508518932,-18.25625));
#470=LINE('',#469,#468);
#471=CARTESIAN_POINT('',(0.756755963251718,-10.5402508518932,-18.25625));
#472=VERTEX_POINT('',#471);
#473=EDGE_CURVE('E318',#256,#472,#470,.T.);
#474=ORIENTED_EDGE('',*,*,#473,.T.);
#475=CARTESIAN_POINT('',(4.0541297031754,-27.9529172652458,-18.25625));
#476=CARTESIAN_POINT('',(3.96113859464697,-27.5384016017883,-18.25625));
#477=CARTESIAN_POINT('',(3.86873255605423,-27.1237547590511,-18.25625));
#478=CARTESIAN_POINT('',(3.68521918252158,-26.2941723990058,-18.25625));
#479=CARTESIAN_POINT('',(3.59411185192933,-25.8792368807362,-18.25625));
#480=CARTESIAN_POINT('',(3.32292449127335,-24.6339289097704,-18.25625));
#481=CARTESIAN_POINT('',(3.14498652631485,-23.8030880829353,-18.25625));
#482=CARTESIAN_POINT('',(2.79593630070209,-22.1391304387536,-18.25625));
#483=CARTESIAN_POINT('',(2.62483081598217,-21.3060121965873,-18.25625));
#484=CARTESIAN_POINT('',(2.29126694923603,-19.6380469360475,-18.25625));
#485=CARTESIAN_POINT('',(2.12880849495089,-18.8031999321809,-18.25625));
#486=CARTESIAN_POINT('',(1.81585669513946,-17.1381367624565,-18.25625));
#487=CARTESIAN_POINT('',(1.66527838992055,-16.3079366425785,-18.25625));
#488=CARTESIAN_POINT('',(1.37718713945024,-14.6452545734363,-18.25625));
#489=CARTESIAN_POINT('',(1.23967424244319,-13.812772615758,-18.25625));
#490=CARTESIAN_POINT('',(0.980801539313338,-12.1453885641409,-18.25625));
#491=CARTESIAN_POINT('',(0.859439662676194,-11.3104867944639,-18.25625));
#492=CARTESIAN_POINT('',(0.636430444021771,-9.63802417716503,-18.25625));
#493=CARTESIAN_POINT('',(0.534783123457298,-8.80046332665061,-18.25625));
#494=CARTESIAN_POINT('',(0.354065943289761,-7.11320346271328,-18.25625));
#495=CARTESIAN_POINT('',(0.275266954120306,-6.26347500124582,-18.25625));
#496=CARTESIAN_POINT('',(0.145673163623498,-4.5618667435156,-18.25625));
#497=CARTESIAN_POINT('',(0.0948777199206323,-3.70998699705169,-18.25625));
#498=CARTESIAN_POINT('',(0.0242527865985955,-2.00531410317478,-18.25625));
#499=CARTESIAN_POINT('',(0.00440895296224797,-1.1525215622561,-18.25625));
#500=CARTESIAN_POINT('',(-0.00309111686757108,0.553206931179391,-18.25625));
#501=CARTESIAN_POINT('',(0.00925260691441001,1.40614288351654,-18.25625));
#502=CARTESIAN_POINT('',(0.0654342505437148,3.11407171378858,-18.25625));
#503=CARTESIAN_POINT('',(0.109386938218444,3.96906073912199,-18.25625));
#504=CARTESIAN_POINT('',(0.226271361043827,5.67703736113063,-18.25625));
#505=CARTESIAN_POINT('',(0.299203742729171,6.53002491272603,-18.25625));
#506=CARTESIAN_POINT('',(0.470346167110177,8.23398996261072,-18.25625));
#507=CARTESIAN_POINT('',(0.568572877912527,9.0849657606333,-18.25625));
#508=CARTESIAN_POINT('',(0.786195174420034,10.78417590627,-18.25625));
#509=CARTESIAN_POINT('',(0.905590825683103,11.6324102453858,-18.25625));
#510=CARTESIAN_POINT('',(1.15416361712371,13.2763112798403,-18.25625));
#511=CARTESIAN_POINT('',(1.28234936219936,14.0721294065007,-18.25625));
#512=CARTESIAN_POINT('',(1.55129184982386,15.6616492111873,-18.25625));
#513=CARTESIAN_POINT('',(1.69204894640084,16.4553508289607,-18.25625));
#514=CARTESIAN_POINT('',(1.98382143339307,18.040942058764,-18.25625));
#515=CARTESIAN_POINT('',(2.13483788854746,18.8328314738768,-18.25625));
#516=CARTESIAN_POINT('',(2.44522268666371,20.4149580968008,-18.25625));
#517=CARTESIAN_POINT('',(2.60459095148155,21.2051953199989,-18.25625));
#518=CARTESIAN_POINT('',(2.93020169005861,22.7844545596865,-18.25625));
#519=CARTESIAN_POINT('',(3.09644587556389,23.5734762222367,-18.25625));
#520=CARTESIAN_POINT('',(3.4345573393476,25.1503125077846,-18.25625));
#521=CARTESIAN_POINT('',(3.60642462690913,25.9381271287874,-18.25625));
#522=CARTESIAN_POINT('',(3.95479981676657,27.5126735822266,-18.25625));
#523=CARTESIAN_POINT('',(4.13130741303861,28.2994054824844,-18.25625));
#524=CARTESIAN_POINT('',(4.48820455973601,29.8719890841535,-18.25625));
#525=CARTESIAN_POINT('',(4.66859412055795,30.6578407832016,-18.25625));
#526=CARTESIAN_POINT('',(5.21101812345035,32.9987298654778,-18.25625));
#527=CARTESIAN_POINT('',(5.57778143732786,34.5526713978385,-18.25625));
#528=CARTESIAN_POINT('',(6.32043421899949,37.6583938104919,-18.25625));
#529=CARTESIAN_POINT('',(6.6963238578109,39.2101746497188,-18.25625));
#530=CARTESIAN_POINT('',(7.45439221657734,42.3101245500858,-18.25625));
#531=CARTESIAN_POINT('',(7.83656241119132,43.8582956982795,-18.25625));
#532=CARTESIAN_POINT('',(8.41365173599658,46.179570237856,-18.25625));
#533=CARTESIAN_POINT('',(8.60665066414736,46.9531520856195,-18.25625));
#534=CARTESIAN_POINT('',(8.99378071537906,48.5000315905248,-18.25625));
#535=CARTESIAN_POINT('',(9.18791183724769,49.2733292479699,-18.25625));
#536=CARTESIAN_POINT('',(9.38253534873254,50.046503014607,-18.25625));
#537=B_SPLINE_CURVE_WITH_KNOTS('',3,(#475,#476,#477,#478,#479,#480,#481,#482,#483,#484,#485,
#486,#487,#488,#489,#490,#491,#492,#493,#494,#495,#496,#497,#498,#499,#500,#501,#502,#503,#504,
#505,#506,#507,#508,#509,#510,#511,#512,#513,#514,#515,#516,#517,#518,#519,#520,#521,#522,#523,
#524,#525,#526,#527,#528,#529,#530,#531,#532,#533,#534,#535,#536),.UNSPECIFIED.,.F.,.F.,(4,2,2,
2,2,2,2,2,2,2,2,2,2,2,2,2,2,2,2,2,2,2,2,2,2,2,2,2,2,2,4),(0.,1.27445408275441,2.54891243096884,
5.09793072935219,7.64941716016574,10.2008822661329,12.7320347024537,15.2631964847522,
17.7940334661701,20.3248732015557,22.8845926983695,25.4442534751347,28.0027276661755,
30.5611986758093,33.1290063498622,35.6968713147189,38.2664327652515,40.8360021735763,
43.2541100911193,45.672286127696,48.0907135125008,50.5091182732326,52.9281287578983,
55.3471432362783,57.7659985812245,60.1848604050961,64.9747269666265,69.7646833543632,
74.5486015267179,76.9404824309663,79.3323607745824),.UNSPECIFIED.);
#538=CARTESIAN_POINT('',(0.,0.,-18.25625));
#539=VERTEX_POINT('',#538);
#540=EDGE_CURVE('E263',#472,#539,#537,.T.);
#541=ORIENTED_EDGE('',*,*,#540,.T.);
#542=EDGE_CURVE('E264',#539,#415,#537,.T.);
#543=ORIENTED_EDGE('',*,*,#542,.T.);
#544=EDGE_LOOP('',(#464,#465,#466,#474,#541,#543));
#545=FACE_BOUND('',#544,.T.);
#546=ADVANCED_FACE('F167',(#545),#463,.T.);
#547=CARTESIAN_POINT('',(20.574,-21.0805017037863,0.));
#548=DIRECTION('',(0.,0.86602540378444,0.499999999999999));
#549=DIRECTION('',(0.,-0.499999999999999,0.866025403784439));
#550=AXIS2_PLACEMENT_3D('',#547,#548,#549);
#551=PLANE('',#550);
#552=ORIENTED_EDGE('',*,*,#249,.F.);
#553=DIRECTION('',(-1.,0.,0.));
#554=VECTOR('',#553,1.);
#555=CARTESIAN_POINT('',(20.574,-21.0805017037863,0.));
#556=LINE('',#555,#554);
#557=CARTESIAN_POINT('',(0.756755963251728,-21.0805017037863,0.));
#558=VERTEX_POINT('',#557);
#559=EDGE_CURVE('E315',#223,#558,#556,.T.);
#560=ORIENTED_EDGE('',*,*,#559,.T.);
#561=CARTESIAN_POINT('',(0.756786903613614,-10.5401353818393,-18.25645));
#562=CARTESIAN_POINT('',(0.698141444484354,-10.7590103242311,-17.8773474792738));
#563=CARTESIAN_POINT('',(0.642182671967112,-10.9780647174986,-17.4979341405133));
#564=CARTESIAN_POINT('',(0.536194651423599,-11.4165422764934,-16.7384687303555));
#565=CARTESIAN_POINT('',(0.486165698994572,-11.6359654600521,-16.3584166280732));
#566=CARTESIAN_POINT('',(0.345782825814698,-12.29492733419,-15.2170611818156));
#567=CARTESIAN_POINT('',(0.265175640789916,-12.7350017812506,-14.4548298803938));
#568=CARTESIAN_POINT('',(0.13455292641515,-13.6140160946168,-12.9323324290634));
#569=CARTESIAN_POINT('',(0.0843816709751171,-14.0529500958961,-12.1720764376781));
#570=CARTESIAN_POINT('',(0.0171084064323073,-14.9313815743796,-10.6505884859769));
#571=CARTESIAN_POINT('',(0.,-15.3708789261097,-9.88935674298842));
#572=CARTESIAN_POINT('',(0.,-16.2498736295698,-8.36689325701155));
#573=CARTESIAN_POINT('',(0.0171084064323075,-16.6893709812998,-7.60566151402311));
#574=CARTESIAN_POINT('',(0.0843816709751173,-17.5678024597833,-6.08417356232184));
#575=CARTESIAN_POINT('',(0.13455292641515,-18.0067364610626,-5.32391757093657));
#576=CARTESIAN_POINT('',(0.265175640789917,-18.8857507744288,-3.80142011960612));
#577=CARTESIAN_POINT('',(0.345782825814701,-19.3258252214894,-3.0391888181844));
#578=CARTESIAN_POINT('',(0.486165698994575,-19.9847870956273,-1.89783337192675));
#579=CARTESIAN_POINT('',(0.536194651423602,-20.204210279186,-1.51778126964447));
#580=CARTESIAN_POINT('',(0.642182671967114,-20.6426878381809,-0.758315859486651));
#581=CARTESIAN_POINT('',(0.698141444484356,-20.8617422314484,-0.378902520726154));
#582=CARTESIAN_POINT('',(0.756786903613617,-21.0806171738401,0.000200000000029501));
#583=B_SPLINE_CURVE_WITH_KNOTS('',3,(#561,#562,#563,#564,#565,#566,#567,#568,#569,#570,#571,
#572,#573,#574,#575,#576,#577,#578,#579,#580,#581,#582),.UNSPECIFIED.,.F.,.F.,(4,2,2,2,2,2,2,2,
2,2,4),(0.,1.32496782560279,2.6500016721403,5.30101714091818,7.93835164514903,10.5751758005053,
13.2119999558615,15.8493344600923,18.5003499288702,19.8253837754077,21.1503516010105),.UNSPECIFIED.);
#584=CARTESIAN_POINT('',(0.,-15.8103762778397,-9.12812499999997));
#585=VERTEX_POINT('',#584);
#586=EDGE_CURVE('E252',#585,#558,#583,.T.);
#587=ORIENTED_EDGE('',*,*,#586,.F.);
#588=EDGE_CURVE('E259',#472,#585,#583,.T.);
#589=ORIENTED_EDGE('',*,*,#588,.F.);
#590=ORIENTED_EDGE('',*,*,#473,.F.);
#591=ORIENTED_EDGE('',*,*,#257,.F.);
#592=EDGE_LOOP('',(#552,#560,#587,#589,#590,#591));
#593=FACE_BOUND('',#592,.T.);
#594=ADVANCED_FACE('F242',(#593),#551,.F.);
#595=CARTESIAN_POINT('',(20.574,-10.5402508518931,18.25625));
#596=DIRECTION('',(0.,0.866025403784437,-0.500000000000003));
#597=DIRECTION('',(0.,0.500000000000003,0.866025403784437));
#598=AXIS2_PLACEMENT_3D('',#595,#596,#597);
#599=PLANE('',#598);
#600=ORIENTED_EDGE('',*,*,#216,.F.);
#601=DIRECTION('',(-1.,0.,0.));
#602=VECTOR('',#601,1.);
#603=CARTESIAN_POINT('',(20.574,-10.5402508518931,18.25625));
#604=LINE('',#603,#602);
#605=CARTESIAN_POINT('',(0.756755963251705,-10.5402508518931,18.25625));
#606=VERTEX_POINT('',#605);
#607=EDGE_CURVE('E312',#190,#606,#604,.T.);
#608=ORIENTED_EDGE('',*,*,#607,.T.);
#609=CARTESIAN_POINT('',(0.756786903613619,-21.0806171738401,-0.000199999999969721));
#610=CARTESIAN_POINT('',(0.698141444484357,-20.8617422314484,0.378902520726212));
#611=CARTESIAN_POINT('',(0.642182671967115,-20.6426878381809,0.758315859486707));
#612=CARTESIAN_POINT('',(0.536194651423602,-20.204210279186,1.51778126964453));
#613=CARTESIAN_POINT('',(0.486165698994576,-19.9847870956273,1.8978333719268));
#614=CARTESIAN_POINT('',(0.3457828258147,-19.3258252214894,3.03918881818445));
#615=CARTESIAN_POINT('',(0.265175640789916,-18.8857507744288,3.80142011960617));
#616=CARTESIAN_POINT('',(0.134552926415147,-18.0067364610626,5.32391757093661));
#617=CARTESIAN_POINT('',(0.0843816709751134,-17.5678024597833,6.08417356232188));
#618=CARTESIAN_POINT('',(0.0171084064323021,-16.6893709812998,7.60566151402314));
#619=CARTESIAN_POINT('',(0.,-16.2498736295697,8.36689325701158));
#620=CARTESIAN_POINT('',(0.,-15.3708789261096,9.88935674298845));
#621=CARTESIAN_POINT('',(0.017108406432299,-14.9313815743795,10.6505884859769));
#622=CARTESIAN_POINT('',(0.0843816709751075,-14.052950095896,12.1720764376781));
#623=CARTESIAN_POINT('',(0.134552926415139,-13.6140160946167,12.9323324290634));
#624=CARTESIAN_POINT('',(0.265175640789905,-12.7350017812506,14.4548298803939));
#625=CARTESIAN_POINT('',(0.345782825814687,-12.29492733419,15.2170611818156));
#626=CARTESIAN_POINT('',(0.486165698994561,-11.6359654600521,16.3584166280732));
#627=CARTESIAN_POINT('',(0.536194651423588,-11.4165422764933,16.7384687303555));
#628=CARTESIAN_POINT('',(0.6421826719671,-10.9780647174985,17.4979341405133));
#629=CARTESIAN_POINT('',(0.698141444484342,-10.759010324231,17.8773474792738));
#630=CARTESIAN_POINT('',(0.756786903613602,-10.5401353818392,18.25645));
#631=B_SPLINE_CURVE_WITH_KNOTS('',3,(#609,#610,#611,#612,#613,#614,#615,#616,#617,#618,#619,
#620,#621,#622,#623,#624,#625,#626,#627,#628,#629,#630),.UNSPECIFIED.,.F.,.F.,(4,2,2,2,2,2,2,2,
2,2,4),(0.,1.32496782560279,2.6500016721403,5.30101714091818,7.93835164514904,10.5751758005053,
13.2119999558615,15.8493344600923,18.5003499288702,19.8253837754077,21.1503516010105),.UNSPECIFIED.);
#632=CARTESIAN_POINT('',(0.,-15.8103762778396,9.12812500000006));
#633=VERTEX_POINT('',#632);
#634=EDGE_CURVE('E190',#633,#606,#631,.T.);
#635=ORIENTED_EDGE('',*,*,#634,.F.);
#636=EDGE_CURVE('E247',#558,#633,#631,.T.);
#637=ORIENTED_EDGE('',*,*,#636,.F.);
#638=ORIENTED_EDGE('',*,*,#559,.F.);
#639=ORIENTED_EDGE('',*,*,#224,.F.);
#640=EDGE_LOOP('',(#600,#608,#635,#637,#638,#639));
#641=FACE_BOUND('',#640,.T.);
#642=ADVANCED_FACE('F238',(#641),#599,.F.);
#643=CARTESIAN_POINT('',(20.574,10.5402508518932,18.25625));
#644=DIRECTION('',(0.,0.,-1.));
#645=DIRECTION('',(0.,1.,0.));
#646=AXIS2_PLACEMENT_3D('',#643,#644,#645);
#647=PLANE('',#646);
#648=ORIENTED_EDGE('',*,*,#398,.F.);
#649=DIRECTION('',(-1.,0.,0.));
#650=VECTOR('',#649,1.);
#651=CARTESIAN_POINT('',(20.574,10.5402508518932,18.25625));
#652=LINE('',#651,#650);
#653=CARTESIAN_POINT('',(0.756755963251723,10.5402508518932,18.25625));
#654=VERTEX_POINT('',#653);
#655=EDGE_CURVE('E309',#395,#654,#652,.T.);
#656=ORIENTED_EDGE('',*,*,#655,.T.);
#657=CARTESIAN_POINT('',(4.05412970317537,-27.9529172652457,18.25625));
#658=CARTESIAN_POINT('',(3.96113859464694,-27.5384016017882,18.25625));
#659=CARTESIAN_POINT('',(3.8687325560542,-27.123754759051,18.25625));
#660=CARTESIAN_POINT('',(3.68521918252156,-26.2941723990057,18.25625));
#661=CARTESIAN_POINT('',(3.5941118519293,-25.8792368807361,18.25625));
#662=CARTESIAN_POINT('',(3.32292449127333,-24.6339289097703,18.25625));
#663=CARTESIAN_POINT('',(3.14498652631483,-23.8030880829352,18.25625));
#664=CARTESIAN_POINT('',(2.79593630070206,-22.1391304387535,18.25625));
#665=CARTESIAN_POINT('',(2.62483081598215,-21.3060121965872,18.25625));
#666=CARTESIAN_POINT('',(2.29126694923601,-19.6380469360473,18.25625));
#667=CARTESIAN_POINT('',(2.12880849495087,-18.8031999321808,18.25625));
#668=CARTESIAN_POINT('',(1.81585669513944,-17.1381367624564,18.25625));
#669=CARTESIAN_POINT('',(1.66527838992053,-16.3079366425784,18.25625));
#670=CARTESIAN_POINT('',(1.37718713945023,-14.6452545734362,18.25625));
#671=CARTESIAN_POINT('',(1.23967424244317,-13.8127726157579,18.25625));
#672=CARTESIAN_POINT('',(0.980801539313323,-12.1453885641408,18.25625));
#673=CARTESIAN_POINT('',(0.859439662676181,-11.3104867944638,18.25625));
#674=CARTESIAN_POINT('',(0.63643044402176,-9.63802417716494,18.25625));
#675=CARTESIAN_POINT('',(0.534783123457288,-8.80046332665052,18.25625));
#676=CARTESIAN_POINT('',(0.354065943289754,-7.11320346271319,18.25625));
#677=CARTESIAN_POINT('',(0.2752669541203,-6.26347500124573,18.25625));
#678=CARTESIAN_POINT('',(0.145673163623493,-4.56186674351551,18.25625));
#679=CARTESIAN_POINT('',(0.0948777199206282,-3.70998699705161,18.25625));
#680=CARTESIAN_POINT('',(0.0242527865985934,-2.0053141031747,18.25625));
#681=CARTESIAN_POINT('',(0.00440895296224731,-1.15252156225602,18.25625));
#682=CARTESIAN_POINT('',(-0.00309111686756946,0.553206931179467,18.25625));
#683=CARTESIAN_POINT('',(0.00925260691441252,1.40614288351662,18.25625));
#684=CARTESIAN_POINT('',(0.0654342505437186,3.11407171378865,18.25625));
#685=CARTESIAN_POINT('',(0.109386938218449,3.96906073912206,18.25625));
#686=CARTESIAN_POINT('',(0.226271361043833,5.6770373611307,18.25625));
#687=CARTESIAN_POINT('',(0.299203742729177,6.5300249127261,18.25625));
#688=CARTESIAN_POINT('',(0.470346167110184,8.23398996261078,18.25625));
#689=CARTESIAN_POINT('',(0.568572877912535,9.08496576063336,18.25625));
#690=CARTESIAN_POINT('',(0.786195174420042,10.7841759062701,18.25625));
#691=CARTESIAN_POINT('',(0.905590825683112,11.6324102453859,18.25625));
#692=CARTESIAN_POINT('',(1.15416361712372,13.2763112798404,18.25625));
#693=CARTESIAN_POINT('',(1.28234936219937,14.0721294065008,18.25625));
#694=CARTESIAN_POINT('',(1.55129184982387,15.6616492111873,18.25625));
#695=CARTESIAN_POINT('',(1.69204894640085,16.4553508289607,18.25625));
#696=CARTESIAN_POINT('',(1.98382143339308,18.040942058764,18.25625));
#697=CARTESIAN_POINT('',(2.13483788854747,18.8328314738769,18.25625));
#698=CARTESIAN_POINT('',(2.44522268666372,20.4149580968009,18.25625));
#699=CARTESIAN_POINT('',(2.60459095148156,21.205195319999,18.25625));
#700=CARTESIAN_POINT('',(2.93020169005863,22.7844545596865,18.25625));
#701=CARTESIAN_POINT('',(3.09644587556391,23.5734762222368,18.25625));
#702=CARTESIAN_POINT('',(3.43455733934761,25.1503125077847,18.25625));
#703=CARTESIAN_POINT('',(3.60642462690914,25.9381271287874,18.25625));
#704=CARTESIAN_POINT('',(3.95479981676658,27.5126735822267,18.25625));
#705=CARTESIAN_POINT('',(4.13130741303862,28.2994054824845,18.25625));
#706=CARTESIAN_POINT('',(4.48820455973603,29.8719890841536,18.25625));
#707=CARTESIAN_POINT('',(4.66859412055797,30.6578407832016,18.25625));
#708=CARTESIAN_POINT('',(5.21101812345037,32.9987298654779,18.25625));
#709=CARTESIAN_POINT('',(5.57778143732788,34.5526713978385,18.25625));
#710=CARTESIAN_POINT('',(6.32043421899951,37.658393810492,18.25625));
#711=CARTESIAN_POINT('',(6.69632385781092,39.2101746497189,18.25625));
#712=CARTESIAN_POINT('',(7.45439221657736,42.3101245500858,18.25625));
#713=CARTESIAN_POINT('',(7.83656241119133,43.8582956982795,18.25625));
#714=CARTESIAN_POINT('',(8.4136517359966,46.179570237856,18.25625));
#715=CARTESIAN_POINT('',(8.60665066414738,46.9531520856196,18.25625));
#716=CARTESIAN_POINT('',(8.99378071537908,48.5000315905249,18.25625));
#717=CARTESIAN_POINT('',(9.18791183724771,49.27332924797,18.25625));
#718=CARTESIAN_POINT('',(9.38253534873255,50.046503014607,18.25625));
#719=B_SPLINE_CURVE_WITH_KNOTS('',3,(#657,#658,#659,#660,#661,#662,#663,#664,#665,#666,#667,
#668,#669,#670,#671,#672,#673,#674,#675,#676,#677,#678,#679,#680,#681,#682,#683,#684,#685,#686,
#687,#688,#689,#690,#691,#692,#693,#694,#695,#696,#697,#698,#699,#700,#701,#702,#703,#704,#705,
#706,#707,#708,#709,#710,#711,#712,#713,#714,#715,#716,#717,#718),.UNSPECIFIED.,.F.,.F.,(4,2,2,
2,2,2,2,2,2,2,2,2,2,2,2,2,2,2,2,2,2,2,2,2,2,2,2,2,2,2,4),(0.,1.27445408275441,2.54891243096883,
5.09793072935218,7.64941716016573,10.2008822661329,12.7320347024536,15.2631964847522,
17.79403346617,20.3248732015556,22.8845926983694,25.4442534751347,28.0027276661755,
30.5611986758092,33.1290063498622,35.6968713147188,38.2664327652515,40.8360021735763,
43.2541100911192,45.672286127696,48.0907135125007,50.5091182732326,52.9281287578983,
55.3471432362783,57.7659985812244,60.1848604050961,64.9747269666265,69.7646833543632,
74.5486015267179,76.9404824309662,79.3323607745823),.UNSPECIFIED.);
#720=CARTESIAN_POINT('',(0.,0.,18.25625));
#721=VERTEX_POINT('',#720);
#722=EDGE_CURVE('E191',#721,#654,#719,.T.);
#723=ORIENTED_EDGE('',*,*,#722,.F.);
#724=EDGE_CURVE('E389',#606,#721,#719,.T.);
#725=ORIENTED_EDGE('',*,*,#724,.F.);
#726=ORIENTED_EDGE('',*,*,#607,.F.);
#727=ORIENTED_EDGE('',*,*,#191,.F.);
#728=EDGE_LOOP('',(#648,#656,#723,#725,#726,#727));
#729=FACE_BOUND('',#728,.T.);
#730=ADVANCED_FACE('F241',(#729),#647,.F.);
#731=CARTESIAN_POINT('',(20.574,21.0805017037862,0.));
#732=DIRECTION('',(0.,-0.86602540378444,-0.499999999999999));
#733=DIRECTION('',(0.,0.499999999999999,-0.866025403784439));
#734=AXIS2_PLACEMENT_3D('',#731,#732,#733);
#735=PLANE('',#734);
#736=ORIENTED_EDGE('',*,*,#386,.F.);
#737=ORIENTED_EDGE('',*,*,#453,.T.);
#738=CARTESIAN_POINT('',(0.756786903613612,10.5401353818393,18.25645));
#739=CARTESIAN_POINT('',(0.698141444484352,10.759010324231,17.8773474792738));
#740=CARTESIAN_POINT('',(0.64218267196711,10.9780647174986,17.4979341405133));
#741=CARTESIAN_POINT('',(0.536194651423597,11.4165422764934,16.7384687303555));
#742=CARTESIAN_POINT('',(0.48616569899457,11.6359654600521,16.3584166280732));
#743=CARTESIAN_POINT('',(0.345782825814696,12.29492733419,15.2170611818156));
#744=CARTESIAN_POINT('',(0.265175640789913,12.7350017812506,14.4548298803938));
#745=CARTESIAN_POINT('',(0.134552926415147,13.6140160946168,12.9323324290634));
#746=CARTESIAN_POINT('',(0.0843816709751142,14.0529500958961,12.1720764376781));
#747=CARTESIAN_POINT('',(0.0171084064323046,14.9313815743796,10.6505884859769));
#748=CARTESIAN_POINT('',(0.,15.3708789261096,9.88935674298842));
#749=CARTESIAN_POINT('',(0.,16.2498736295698,8.36689325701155));
#750=CARTESIAN_POINT('',(0.0171084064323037,16.6893709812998,7.60566151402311));
#751=CARTESIAN_POINT('',(0.0843816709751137,17.5678024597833,6.08417356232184));
#752=CARTESIAN_POINT('',(0.134552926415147,18.0067364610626,5.32391757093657));
#753=CARTESIAN_POINT('',(0.265175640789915,18.8857507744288,3.80142011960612));
#754=CARTESIAN_POINT('',(0.345782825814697,19.3258252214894,3.0391888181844));
#755=CARTESIAN_POINT('',(0.486165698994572,19.9847870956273,1.89783337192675));
#756=CARTESIAN_POINT('',(0.536194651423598,20.204210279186,1.51778126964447));
#757=CARTESIAN_POINT('',(0.642182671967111,20.6426878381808,0.758315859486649));
#758=CARTESIAN_POINT('',(0.698141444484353,20.8617422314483,0.378902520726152));
#759=CARTESIAN_POINT('',(0.756786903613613,21.0806171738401,-0.000200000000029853));
#760=B_SPLINE_CURVE_WITH_KNOTS('',3,(#738,#739,#740,#741,#742,#743,#744,#745,#746,#747,#748,
#749,#750,#751,#752,#753,#754,#755,#756,#757,#758,#759),.UNSPECIFIED.,.F.,.F.,(4,2,2,2,2,2,2,2,
2,2,4),(0.,1.32496782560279,2.6500016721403,5.30101714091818,7.93835164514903,10.5751758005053,
13.2119999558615,15.8493344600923,18.5003499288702,19.8253837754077,21.1503516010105),.UNSPECIFIED.);
#761=CARTESIAN_POINT('',(0.,15.8103762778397,9.12812499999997));
#762=VERTEX_POINT('',#761);
#763=EDGE_CURVE('E253',#762,#446,#760,.T.);
#764=ORIENTED_EDGE('',*,*,#763,.F.);
#765=EDGE_CURVE('E258',#654,#762,#760,.T.);
#766=ORIENTED_EDGE('',*,*,#765,.F.);
#767=ORIENTED_EDGE('',*,*,#655,.F.);
#768=ORIENTED_EDGE('',*,*,#396,.F.);
#769=EDGE_LOOP('',(#736,#737,#764,#766,#767,#768));
#770=FACE_BOUND('',#769,.T.);
#771=ADVANCED_FACE('F34',(#770),#735,.F.);
#772=CARTESIAN_POINT('',(0.,0.,0.));
#773=DIRECTION('',(1.,0.,0.));
#774=DIRECTION('',(0.,0.,-1.));
#775=AXIS2_PLACEMENT_3D('',#772,#773,#774);
#776=CONICAL_SURFACE('',#775,18.25625,1.30899693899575);
#777=ORIENTED_EDGE('',*,*,#634,.T.);
#778=ORIENTED_EDGE('',*,*,#724,.T.);
#779=CARTESIAN_POINT('',(0.,0.,0.));
#780=DIRECTION('',(-1.,0.,0.));
#781=DIRECTION('',(0.,0.,1.));
#782=AXIS2_PLACEMENT_3D('',#779,#780,#781);
#783=CIRCLE('',#782,18.25625);
#784=EDGE_CURVE('E304',#633,#721,#783,.T.);
#785=ORIENTED_EDGE('',*,*,#784,.F.);
#786=EDGE_LOOP('',(#777,#778,#785));
#787=FACE_BOUND('',#786,.T.);
#788=ADVANCED_FACE('F388',(#787),#776,.T.);
#789=ORIENTED_EDGE('',*,*,#636,.T.);
#790=EDGE_CURVE('E307',#585,#633,#783,.T.);
#791=ORIENTED_EDGE('',*,*,#790,.F.);
#792=ORIENTED_EDGE('',*,*,#586,.T.);
#793=EDGE_LOOP('',(#789,#791,#792));
#794=FACE_BOUND('',#793,.T.);
#795=ADVANCED_FACE('F390',(#794),#776,.T.);
#796=ORIENTED_EDGE('',*,*,#588,.T.);
#797=EDGE_CURVE('E374',#539,#585,#783,.T.);
#798=ORIENTED_EDGE('',*,*,#797,.F.);
#799=ORIENTED_EDGE('',*,*,#540,.F.);
#800=EDGE_LOOP('',(#796,#798,#799));
#801=FACE_BOUND('',#800,.T.);
#802=ADVANCED_FACE('F371',(#801),#776,.T.);
#803=EDGE_CURVE('E383',#442,#539,#783,.T.);
#804=ORIENTED_EDGE('',*,*,#803,.F.);
#805=ORIENTED_EDGE('',*,*,#443,.T.);
#806=ORIENTED_EDGE('',*,*,#542,.F.);
#807=EDGE_LOOP('',(#804,#805,#806));
#808=FACE_BOUND('',#807,.T.);
#809=ADVANCED_FACE('F208',(#808),#776,.T.);
#810=ORIENTED_EDGE('',*,*,#763,.T.);
#811=ORIENTED_EDGE('',*,*,#447,.T.);
#812=EDGE_CURVE('E303',#762,#442,#783,.T.);
#813=ORIENTED_EDGE('',*,*,#812,.F.);
#814=EDGE_LOOP('',(#810,#811,#813));
#815=FACE_BOUND('',#814,.T.);
#816=ADVANCED_FACE('F381',(#815),#776,.T.);
#817=ORIENTED_EDGE('',*,*,#722,.T.);
#818=ORIENTED_EDGE('',*,*,#765,.T.);
#819=CARTESIAN_POINT('',(0.,0.,0.));
#820=DIRECTION('',(-1.,0.,0.));
#821=DIRECTION('',(0.,0.,1.));
#822=AXIS2_PLACEMENT_3D('',#819,#820,#821);
#823=CIRCLE('',#822,18.25625);
#824=EDGE_CURVE('E282',#721,#762,#823,.T.);
#825=ORIENTED_EDGE('',*,*,#824,.F.);
#826=EDGE_LOOP('',(#817,#818,#825));
#827=FACE_BOUND('',#826,.T.);
#828=ADVANCED_FACE('F161',(#827),#776,.T.);
#829=CARTESIAN_POINT('',(0.,21.0805017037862,0.));
#830=DIRECTION('',(-1.,0.,0.));
#831=DIRECTION('',(0.,0.,1.));
#832=AXIS2_PLACEMENT_3D('',#829,#830,#831);
#833=PLANE('',#832);
#834=CARTESIAN_POINT('',(0.,0.,0.));
#835=DIRECTION('',(-1.,0.,0.));
#836=DIRECTION('',(0.,0.,1.));
#837=AXIS2_PLACEMENT_3D('',#834,#835,#836);
#838=CIRCLE('',#837,12.7);
#839=CARTESIAN_POINT('',(0.,0.,12.7));
#840=VERTEX_POINT('',#839);
#841=EDGE_CURVE('E37',#840,#840,#838,.T.);
#842=ORIENTED_EDGE('',*,*,#841,.F.);
#843=EDGE_LOOP('',(#842));
#844=FACE_BOUND('',#843,.T.);
#845=ORIENTED_EDGE('',*,*,#784,.T.);
#846=ORIENTED_EDGE('',*,*,#824,.T.);
#847=ORIENTED_EDGE('',*,*,#812,.T.);
#848=ORIENTED_EDGE('',*,*,#803,.T.);
#849=ORIENTED_EDGE('',*,*,#797,.T.);
#850=ORIENTED_EDGE('',*,*,#790,.T.);
#851=EDGE_LOOP('',(#845,#846,#847,#848,#849,#850));
#852=FACE_BOUND('',#851,.T.);
#853=ADVANCED_FACE('F158',(#844,#852),#833,.T.);
#854=CARTESIAN_POINT('',(1.2481374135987,0.,0.));
#855=DIRECTION('',(-1.,0.,0.));
#856=DIRECTION('',(0.,0.,1.));
#857=AXIS2_PLACEMENT_3D('',#854,#855,#856);
#858=CONICAL_SURFACE('',#857,10.95375,0.959931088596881);
#859=CARTESIAN_POINT('',(1.13697946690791,0.,0.));
#860=DIRECTION('',(-1.,0.,0.));
#861=DIRECTION('',(0.,0.,1.));
#862=AXIS2_PLACEMENT_3D('',#859,#860,#861);
#863=CIRCLE('',#862,11.1125);
#864=CARTESIAN_POINT('',(1.13697946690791,0.,11.1125));
#865=VERTEX_POINT('',#864);
#866=EDGE_CURVE('E293',#865,#865,#863,.F.);
#867=ORIENTED_EDGE('',*,*,#866,.T.);
#868=EDGE_LOOP('',(#867));
#869=FACE_BOUND('',#868,.T.);
#870=CARTESIAN_POINT('',(0.0253999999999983,0.,0.));
#871=DIRECTION('',(1.,0.,0.));
#872=DIRECTION('',(0.,0.,-1.));
#873=AXIS2_PLACEMENT_3D('',#870,#871,#872);
#874=CIRCLE('',#873,12.7);
#875=CARTESIAN_POINT('',(0.0253999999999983,0.,-12.7));
#876=VERTEX_POINT('',#875);
#877=EDGE_CURVE('E291',#876,#876,#874,.T.);
#878=ORIENTED_EDGE('',*,*,#877,.F.);
#879=EDGE_LOOP('',(#878));
#880=FACE_BOUND('',#879,.T.);
#881=ADVANCED_FACE('F139',(#869,#880),#858,.F.);
#882=CARTESIAN_POINT('',(-3.175,0.,0.));
#883=DIRECTION('',(1.,0.,0.));
#884=DIRECTION('',(0.,0.,-1.));
#885=AXIS2_PLACEMENT_3D('',#882,#883,#884);
#886=CYLINDRICAL_SURFACE('',#885,12.7);
#887=ORIENTED_EDGE('',*,*,#841,.T.);
#888=EDGE_LOOP('',(#887));
#889=FACE_BOUND('',#888,.T.);
#890=ORIENTED_EDGE('',*,*,#877,.T.);
#891=EDGE_LOOP('',(#890));
#892=FACE_BOUND('',#891,.T.);
#893=ADVANCED_FACE('F130',(#889,#892),#886,.F.);
#894=CARTESIAN_POINT('',(41.7290636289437,0.,0.));
#895=DIRECTION('',(-1.,0.,0.));
#896=DIRECTION('',(0.,0.,1.));
#897=AXIS2_PLACEMENT_3D('',#894,#895,#896);
#898=CONICAL_SURFACE('',#897,0.,1.02974425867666);
#899=CARTESIAN_POINT('',(35.052,0.,0.));
#900=DIRECTION('',(-1.,0.,0.));
#901=DIRECTION('',(0.,0.,1.));
#902=AXIS2_PLACEMENT_3D('',#899,#900,#901);
#903=CIRCLE('',#902,11.1125);
#904=CARTESIAN_POINT('',(35.052,0.,11.1125));
#905=VERTEX_POINT('',#904);
#906=EDGE_CURVE('E287',#905,#905,#903,.T.);
#907=ORIENTED_EDGE('',*,*,#906,.T.);
#908=EDGE_LOOP('',(#907));
#909=FACE_BOUND('',#908,.T.);
#910=CARTESIAN_POINT('',(41.7290636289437,0.,0.));
#911=VERTEX_POINT('',#910);
#912=VERTEX_LOOP('',#911);
#913=FACE_BOUND('',#912,.T.);
#914=ADVANCED_FACE('F127',(#909,#913),#898,.F.);
#915=CARTESIAN_POINT('',(0.,0.,0.));
#916=DIRECTION('',(-1.,0.,0.));
#917=DIRECTION('',(0.,0.,1.));
#918=AXIS2_PLACEMENT_3D('',#915,#916,#917);
#919=CYLINDRICAL_SURFACE('',#918,11.1125);
#920=ORIENTED_EDGE('',*,*,#866,.F.);
#921=EDGE_LOOP('',(#920));
#922=FACE_BOUND('',#921,.T.);
#923=ORIENTED_EDGE('',*,*,#906,.F.);
#924=EDGE_LOOP('',(#923));
#925=FACE_BOUND('',#924,.T.);
#926=ADVANCED_FACE('F129',(#922,#925),#919,.F.);
#927=CLOSED_SHELL('',(#71,#91,#111,#120,#221,#254,#327,#360,#393,#403,#458,#546,#594,#642,#730,
#771,#788,#795,#802,#809,#816,#828,#853,#881,#893,#914,#926));
#928=MANIFOLD_SOLID_BREP('B2',#927);
#929=ADVANCED_BREP_SHAPE_REPRESENTATION('',(#18,#928),#14);
#930=SHAPE_DEFINITION_REPRESENTATION(#9,#929);
ENDSEC;
END-ISO-10303-21;
